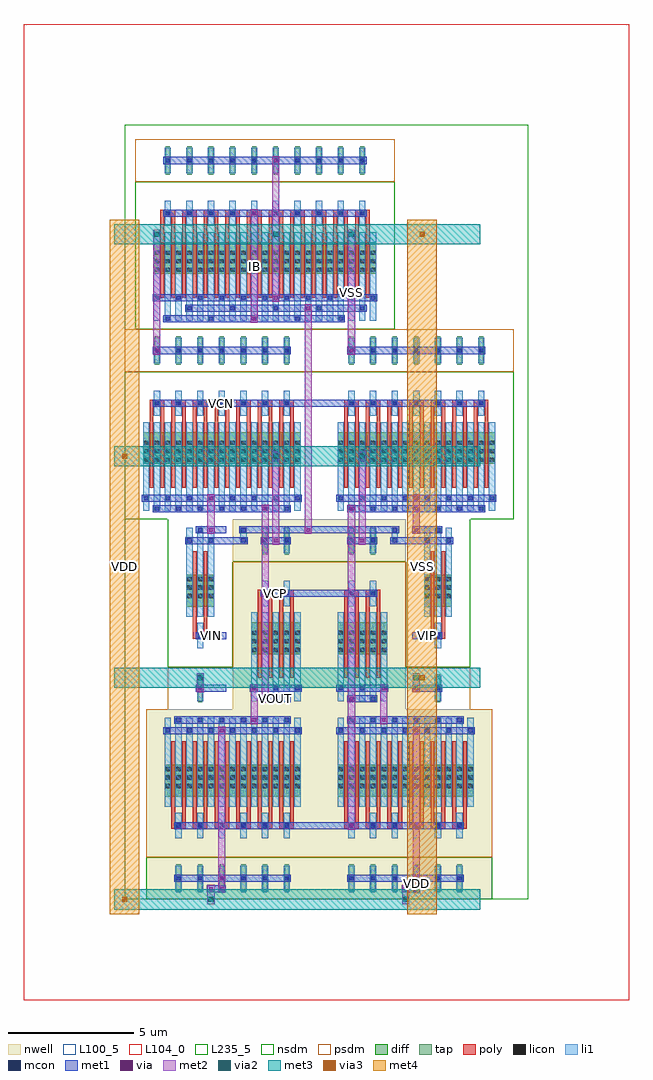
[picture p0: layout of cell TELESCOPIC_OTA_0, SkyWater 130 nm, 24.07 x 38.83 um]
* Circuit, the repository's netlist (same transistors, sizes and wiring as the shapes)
* NGSPICE file created from TELESCOPIC_OTA_0.ext - technology: sky130A

.subckt PMOS_S_86315193_X6_Y1_1774869361 a_230_441# a_200_252# w_0_0#
X0 w_0_0# a_200_252# a_230_441# w_0_0# sky130_fd_pr__pfet_01v8 ad=0.1764 pd=1.54 as=0.1764 ps=1.54 w=1.26 l=0.15 M=12
.ends

.subckt NMOS_4T_67607497_X1_Y1_1774869359 a_230_441# a_200_252# a_147_441# a_241_1232#
X0 a_230_441# a_200_252# a_147_441# a_241_1232# sky130_fd_pr__nfet_01v8 ad=0.1764 pd=1.54 as=0.3339 ps=3.05 w=1.26 l=0.15 M=2
.ends

.subckt SCM_NMOS_71172734_X5_Y1_1774869362 a_402_441# a_200_252# a_147_441#
X0 a_147_441# a_200_252# a_200_252# a_147_441# sky130_fd_pr__nfet_01v8 ad=0.1764 pd=1.54 as=0.1764 ps=1.54 w=1.26 l=0.15 M=10
X1 a_402_441# a_200_252# a_147_441# a_147_441# sky130_fd_pr__nfet_01v8 ad=0.1764 pd=1.54 as=0.1764 ps=1.54 w=1.26 l=0.15 M=10
.ends

.subckt PMOS_4T_36899923_X2_Y1_1774869360 a_230_441# a_200_252# a_147_441# w_0_0#
X0 a_147_441# a_200_252# a_230_441# w_0_0# sky130_fd_pr__pfet_01v8 ad=0.1764 pd=1.54 as=0.1764 ps=1.54 w=1.26 l=0.15 M=4
.ends

.subckt NMOS_4T_35702222_X7_Y1_1774869358 a_230_441# a_200_252# a_147_441# a_241_1232#
X0 a_147_441# a_200_252# a_230_441# a_241_1232# sky130_fd_pr__nfet_01v8 ad=0.1764 pd=1.54 as=0.1764 ps=1.54 w=1.26 l=0.15 M=14
.ends

.subckt TELESCOPIC_OTA_0 IB VCN VOUT VIP VIN VCP VSS VDD
XPMOS_S_86315193_X6_Y1_1774869361_0 m1_1000_1400# m1_1290_560# VDD PMOS_S_86315193_X6_Y1_1774869361
XNMOS_4T_67607497_X1_Y1_1774869359_0 m1_656_2912# VIN li_921_2839# VSS NMOS_4T_67607497_X1_Y1_1774869359
XSCM_NMOS_71172734_X5_Y1_1774869362_0 li_921_2839# IB VSS SCM_NMOS_71172734_X5_Y1_1774869362
XPMOS_S_86315193_X6_Y1_1774869361_1 m1_2032_1400# m1_1290_560# VDD PMOS_S_86315193_X6_Y1_1774869361
XNMOS_4T_67607497_X1_Y1_1774869359_1 m1_2290_2912# VIP li_921_2839# VSS NMOS_4T_67607497_X1_Y1_1774869359
XPMOS_4T_36899923_X2_Y1_1774869360_0 VOUT VCP m1_1000_1400# VDD PMOS_4T_36899923_X2_Y1_1774869360
XPMOS_4T_36899923_X2_Y1_1774869360_1 m1_1290_560# VCP m1_2032_1400# VDD PMOS_4T_36899923_X2_Y1_1774869360
XNMOS_4T_35702222_X7_Y1_1774869358_0 VOUT VCN m1_656_2912# VSS NMOS_4T_35702222_X7_Y1_1774869358
XNMOS_4T_35702222_X7_Y1_1774869358_1 m1_1290_560# VCN m1_2290_2912# VSS NMOS_4T_35702222_X7_Y1_1774869358
.ends

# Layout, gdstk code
from math import pi, radians
import gdstk
lib = gdstk.Library(unit=1e-6, precision=1e-09)
def R(c, l, rs):  # rectangles x0, y0, x1, y1
    for r in rs: c.add(gdstk.rectangle(r[:2], r[2:], *l))
def A(c, l, x, y, w, h, nx, ny, dx, dy):  # array of equal rectangles
    R(c, l, [(x+i*dx, y+j*dy, x+i*dx+w, y+j*dy+h) for i in range(nx) for j in range(ny)])
def P(c, l, *ps):  # polygons
    for p in ps: c.add(gdstk.Polygon(p, *l))
nwell = (64, 20)
diff = (65, 20)
tap = (65, 44)
poly = (66, 20)
licon = (66, 44)
li1 = (67, 20)
mcon = (67, 44)
met1 = (68, 20)
via = (68, 44)
met2 = (69, 20)
via2 = (69, 44)
met3 = (70, 20)
via3 = (70, 44)
met4 = (71, 20)
nsdm = (93, 44)
psdm = (94, 20)
L100_5 = (100, 5)
L104_0 = (104, 0)
L235_5 = (235, 5)

scm_nmos_71172734_x5_y1_ = lib.new_cell('SCM_NMOS_71172734_X5_Y1_1774869362')
R(scm_nmos_71172734_x5_y1_, diff, [(0.735,2.205,9.585,3.465)])
A(scm_nmos_71172734_x5_y1_, tap, 1.205, 6.16, 0.17, 1.12, 10, 1, 0.86, 0)
A(scm_nmos_71172734_x5_y1_, poly, 1, 1.26, 0.15, 3.36, 20, 1, 0.43, 0)
A(scm_nmos_71172734_x5_y1_, poly, 1, 4.485, 0.58, 0.27, 10, 1, 0.86, 0)
A(scm_nmos_71172734_x5_y1_, licon, 0.775, 2.285, 0.17, 0.17, 3, 3, 0.43, 0.34)
A(scm_nmos_71172734_x5_y1_, licon, 1.635, 2.285, 0.17, 0.17, 3, 3, 0.43, 0.34)
A(scm_nmos_71172734_x5_y1_, licon, 2.495, 2.285, 0.17, 0.17, 3, 3, 0.43, 0.34)
A(scm_nmos_71172734_x5_y1_, licon, 3.355, 2.285, 0.17, 0.17, 3, 3, 0.43, 0.34)
A(scm_nmos_71172734_x5_y1_, licon, 4.215, 2.285, 0.17, 0.17, 3, 3, 0.43, 0.34)
A(scm_nmos_71172734_x5_y1_, licon, 5.075, 2.285, 0.17, 0.17, 3, 3, 0.43, 0.34)
A(scm_nmos_71172734_x5_y1_, licon, 5.935, 2.285, 0.17, 0.17, 3, 3, 0.43, 0.34)
A(scm_nmos_71172734_x5_y1_, licon, 6.795, 2.285, 0.17, 0.17, 3, 3, 0.43, 0.34)
A(scm_nmos_71172734_x5_y1_, licon, 7.655, 2.285, 0.17, 0.17, 3, 3, 0.43, 0.34)
A(scm_nmos_71172734_x5_y1_, licon, 8.515, 2.285, 0.17, 0.17, 3, 3, 0.43, 0.34)
A(scm_nmos_71172734_x5_y1_, licon, 1.205, 4.535, 0.17, 0.17, 10, 2, 0.86, 2.1)
A(scm_nmos_71172734_x5_y1_, li1, 0.735, 0.335, 0.25, 3.53, 21, 1, 0.43, 0)
A(scm_nmos_71172734_x5_y1_, li1, 1.165, 4.115, 0.25, 1.01, 10, 2, 0.86, 2.1)
A(scm_nmos_71172734_x5_y1_, mcon, 1.205, 0.335, 0.17, 0.17, 5, 1, 1.72, 0)
A(scm_nmos_71172734_x5_y1_, mcon, 2.065, 0.755, 0.17, 0.17, 5, 1, 1.72, 0)
A(scm_nmos_71172734_x5_y1_, mcon, 0.775, 1.175, 0.17, 0.17, 11, 1, 0.86, 0)
A(scm_nmos_71172734_x5_y1_, mcon, 1.205, 4.535, 0.17, 0.17, 10, 2, 0.86, 2.1)
R(scm_nmos_71172734_x5_y1_, met1, [(1.12,0.28,8.34,0.56), (1.98,0.7,9.2,0.98), (0.69,1.12,9.63,1.4), (1.12,4.48,9.2,4.76), (1.12,6.58,9.2,6.86)])
R(scm_nmos_71172734_x5_y1_, via, [(4.655,0.345,4.805,0.495), (5.515,1.185,5.665,1.335), (4.655,4.545,4.805,4.695), (5.515,6.645,5.665,6.795)])
R(scm_nmos_71172734_x5_y1_, met2, [(4.59,0.26,4.87,4.78), (5.45,1.1,5.73,6.88)])
R(scm_nmos_71172734_x5_y1_, nsdm, [(0,0,10.32,5.88)])
R(scm_nmos_71172734_x5_y1_, psdm, [(0,5.88,10.32,7.56)])
R(scm_nmos_71172734_x5_y1_, L100_5, [(0,0,10.32,7.56)])

pmos_s_86315193_x6_y1_17 = lib.new_cell('PMOS_S_86315193_X6_Y1_1774869361')
R(pmos_s_86315193_x6_y1_17, nwell, [(0,0,6.88,7.56)])
R(pmos_s_86315193_x6_y1_17, diff, [(0.735,2.205,6.145,3.465)])
A(pmos_s_86315193_x6_y1_17, tap, 1.205, 6.16, 0.17, 1.12, 6, 1, 0.86, 0)
A(pmos_s_86315193_x6_y1_17, poly, 1, 1.26, 0.15, 3.36, 12, 1, 0.43, 0)
A(pmos_s_86315193_x6_y1_17, poly, 1, 4.485, 0.58, 0.27, 6, 1, 0.86, 0)
A(pmos_s_86315193_x6_y1_17, licon, 0.775, 2.285, 0.17, 0.17, 3, 3, 0.43, 0.34)
A(pmos_s_86315193_x6_y1_17, licon, 1.635, 2.285, 0.17, 0.17, 3, 3, 0.43, 0.34)
A(pmos_s_86315193_x6_y1_17, licon, 2.495, 2.285, 0.17, 0.17, 3, 3, 0.43, 0.34)
A(pmos_s_86315193_x6_y1_17, licon, 3.355, 2.285, 0.17, 0.17, 3, 3, 0.43, 0.34)
A(pmos_s_86315193_x6_y1_17, licon, 4.215, 2.285, 0.17, 0.17, 3, 3, 0.43, 0.34)
A(pmos_s_86315193_x6_y1_17, licon, 5.075, 2.285, 0.17, 0.17, 3, 3, 0.43, 0.34)
A(pmos_s_86315193_x6_y1_17, licon, 1.205, 4.535, 0.17, 0.17, 6, 2, 0.86, 2.1)
A(pmos_s_86315193_x6_y1_17, li1, 0.735, 0.335, 0.25, 3.53, 13, 1, 0.43, 0)
A(pmos_s_86315193_x6_y1_17, li1, 1.165, 4.115, 0.25, 1.01, 6, 2, 0.86, 2.1)
A(pmos_s_86315193_x6_y1_17, mcon, 1.205, 0.335, 0.17, 0.17, 6, 2, 0.86, 4.2)
A(pmos_s_86315193_x6_y1_17, mcon, 0.775, 0.755, 0.17, 0.17, 7, 1, 0.86, 0)
A(pmos_s_86315193_x6_y1_17, mcon, 1.205, 6.635, 0.17, 0.17, 6, 1, 0.86, 0)
R(pmos_s_86315193_x6_y1_17, met1, [(1.12,0.28,5.76,0.56), (0.69,0.7,6.19,0.98), (1.12,4.48,5.76,4.76), (1.12,6.58,5.76,6.86)])
R(pmos_s_86315193_x6_y1_17, via, [(3.795,0.765,3.945,0.915), (3.795,6.645,3.945,6.795)])
R(pmos_s_86315193_x6_y1_17, met2, [(3.73,0.68,4.01,6.88)])
R(pmos_s_86315193_x6_y1_17, nsdm, [(0,5.88,6.88,7.56)])
R(pmos_s_86315193_x6_y1_17, psdm, [(0,0,6.88,5.88)])
R(pmos_s_86315193_x6_y1_17, L100_5, [(0,0,6.88,7.56)])

nmos_4t_35702222_x7_y1_1 = lib.new_cell('NMOS_4T_35702222_X7_Y1_1774869358')
R(nmos_4t_35702222_x7_y1_1, diff, [(0.735,2.205,7.005,3.465)])
A(nmos_4t_35702222_x7_y1_1, tap, 1.205, 6.16, 0.17, 1.12, 7, 1, 0.86, 0)
A(nmos_4t_35702222_x7_y1_1, poly, 1, 1.26, 0.15, 3.36, 14, 1, 0.43, 0)
A(nmos_4t_35702222_x7_y1_1, poly, 1, 4.485, 0.58, 0.27, 7, 1, 0.86, 0)
A(nmos_4t_35702222_x7_y1_1, licon, 0.775, 2.285, 0.17, 0.17, 3, 3, 0.43, 0.34)
A(nmos_4t_35702222_x7_y1_1, licon, 1.635, 2.285, 0.17, 0.17, 3, 3, 0.43, 0.34)
A(nmos_4t_35702222_x7_y1_1, licon, 2.495, 2.285, 0.17, 0.17, 3, 3, 0.43, 0.34)
A(nmos_4t_35702222_x7_y1_1, licon, 3.355, 2.285, 0.17, 0.17, 3, 3, 0.43, 0.34)
A(nmos_4t_35702222_x7_y1_1, licon, 4.215, 2.285, 0.17, 0.17, 3, 3, 0.43, 0.34)
A(nmos_4t_35702222_x7_y1_1, licon, 5.075, 2.285, 0.17, 0.17, 3, 3, 0.43, 0.34)
A(nmos_4t_35702222_x7_y1_1, licon, 5.935, 2.285, 0.17, 0.17, 3, 3, 0.43, 0.34)
A(nmos_4t_35702222_x7_y1_1, licon, 1.205, 4.535, 0.17, 0.17, 7, 2, 0.86, 2.1)
A(nmos_4t_35702222_x7_y1_1, li1, 0.735, 0.335, 0.25, 3.53, 15, 1, 0.43, 0)
A(nmos_4t_35702222_x7_y1_1, li1, 1.165, 4.115, 0.25, 1.01, 7, 2, 0.86, 2.1)
A(nmos_4t_35702222_x7_y1_1, mcon, 1.205, 0.335, 0.17, 0.17, 7, 2, 0.86, 4.2)
A(nmos_4t_35702222_x7_y1_1, mcon, 0.775, 0.755, 0.17, 0.17, 8, 1, 0.86, 0)
A(nmos_4t_35702222_x7_y1_1, mcon, 1.205, 6.635, 0.17, 0.17, 7, 1, 0.86, 0)
R(nmos_4t_35702222_x7_y1_1, met1, [(1.12,0.28,6.62,0.56), (0.69,0.7,7.05,0.98), (1.12,4.48,6.62,4.76), (1.12,6.58,6.62,6.86)])
R(nmos_4t_35702222_x7_y1_1, nsdm, [(0,0,7.74,5.88)])
R(nmos_4t_35702222_x7_y1_1, psdm, [(0,5.88,7.74,7.56)])
R(nmos_4t_35702222_x7_y1_1, L100_5, [(0,0,7.74,7.56)])

nmos_4t_67607497_x1_y1_1 = lib.new_cell('NMOS_4T_67607497_X1_Y1_1774869359')
R(nmos_4t_67607497_x1_y1_1, diff, [(0.735,2.205,1.845,3.465)])
R(nmos_4t_67607497_x1_y1_1, tap, [(1.205,6.16,1.375,7.28)])
R(nmos_4t_67607497_x1_y1_1, poly, [(1,1.26,1.15,4.62), (1.43,1.26,1.58,4.62), (1,4.485,1.58,4.755)])
A(nmos_4t_67607497_x1_y1_1, licon, 0.775, 2.285, 0.17, 0.17, 3, 3, 0.43, 0.34)
R(nmos_4t_67607497_x1_y1_1, licon, [(1.205,4.535,1.375,4.705), (1.205,6.635,1.375,6.805)])
A(nmos_4t_67607497_x1_y1_1, li1, 0.735, 0.335, 0.25, 3.53, 3, 1, 0.43, 0)
R(nmos_4t_67607497_x1_y1_1, li1, [(1.165,4.115,1.415,5.125), (1.165,6.215,1.415,7.225)])
R(nmos_4t_67607497_x1_y1_1, mcon, [(1.205,0.335,1.375,0.505), (0.775,0.755,0.945,0.925), (1.635,0.755,1.805,0.925), (1.205,4.535,1.375,4.705), (1.205,6.635,1.375,6.805)])
R(nmos_4t_67607497_x1_y1_1, met1, [(0.26,0.28,1.46,0.56), (0.69,0.7,1.89,0.98), (0.26,4.48,1.46,4.76), (0.26,6.58,1.46,6.86)])
R(nmos_4t_67607497_x1_y1_1, nsdm, [(0,0,2.58,5.88)])
R(nmos_4t_67607497_x1_y1_1, psdm, [(0,5.88,2.58,7.56)])
R(nmos_4t_67607497_x1_y1_1, L100_5, [(0,0,2.58,7.56)])

pmos_4t_36899923_x2_y1_1 = lib.new_cell('PMOS_4T_36899923_X2_Y1_1774869360')
R(pmos_4t_36899923_x2_y1_1, nwell, [(0,0,3.44,7.56)])
R(pmos_4t_36899923_x2_y1_1, diff, [(0.735,2.205,2.705,3.465)])
R(pmos_4t_36899923_x2_y1_1, tap, [(1.205,6.16,1.375,7.28), (2.065,6.16,2.235,7.28)])
A(pmos_4t_36899923_x2_y1_1, poly, 1, 1.26, 0.15, 3.36, 4, 1, 0.43, 0)
R(pmos_4t_36899923_x2_y1_1, poly, [(1,4.485,1.58,4.755), (1.86,4.485,2.44,4.755)])
A(pmos_4t_36899923_x2_y1_1, licon, 0.775, 2.285, 0.17, 0.17, 3, 3, 0.43, 0.34)
A(pmos_4t_36899923_x2_y1_1, licon, 1.635, 2.285, 0.17, 0.17, 3, 3, 0.43, 0.34)
R(pmos_4t_36899923_x2_y1_1, licon, [(1.205,4.535,1.375,4.705), (2.065,4.535,2.235,4.705), (1.205,6.635,1.375,6.805), (2.065,6.635,2.235,6.805)])
A(pmos_4t_36899923_x2_y1_1, li1, 0.735, 0.335, 0.25, 3.53, 5, 1, 0.43, 0)
R(pmos_4t_36899923_x2_y1_1, li1, [(1.165,4.115,1.415,5.125), (2.025,4.115,2.275,5.125), (1.165,6.215,1.415,7.225), (2.025,6.215,2.275,7.225)])
A(pmos_4t_36899923_x2_y1_1, mcon, 0.775, 0.755, 0.17, 0.17, 3, 1, 0.86, 0)
R(pmos_4t_36899923_x2_y1_1, mcon, [(1.205,0.335,1.375,0.505), (2.065,0.335,2.235,0.505), (1.205,4.535,1.375,4.705), (2.065,4.535,2.235,4.705), (1.205,6.635,1.375,6.805), (2.065,6.635,2.235,6.805)])
R(pmos_4t_36899923_x2_y1_1, met1, [(1.12,0.28,2.32,0.56), (0.69,0.7,2.75,0.98), (1.12,4.48,2.32,4.76), (1.12,6.58,2.32,6.86)])
R(pmos_4t_36899923_x2_y1_1, nsdm, [(0,5.88,3.44,7.56)])
R(pmos_4t_36899923_x2_y1_1, psdm, [(0,0,3.44,5.88)])
R(pmos_4t_36899923_x2_y1_1, L100_5, [(0,0,3.44,7.56)])

telescopic_ota_0 = lib.new_cell('TELESCOPIC_OTA_0')
R(telescopic_ota_0, li1, [(4.605,14.195,4.855,14.365), (4.605,14.195,4.855,14.365), (4.605,14.195,4.855,14.365), (4.605,14.195,4.855,14.365), (10.625,14.195,10.875,14.365), (10.625,14.195,10.875,14.365), (10.625,14.195,10.875,14.365), (10.625,14.195,10.875,14.365), (4.605,14.28,4.855,14.7), (10.625,14.28,10.875,14.7), (4.605,14.615,4.855,14.785), (4.605,14.615,4.855,14.785), (4.605,14.615,4.855,14.785), (4.605,14.615,4.855,14.785), (10.625,14.615,10.875,14.785), (10.625,14.615,10.875,14.785), (10.625,14.615,10.875,14.785), (10.625,14.615,10.875,14.785)])
R(telescopic_ota_0, mcon, [(4.645,14.195,4.815,14.365), (4.645,14.195,4.815,14.365), (4.645,14.195,4.815,14.365), (4.645,14.195,4.815,14.365), (10.665,14.195,10.835,14.365), (10.665,14.195,10.835,14.365), (10.665,14.195,10.835,14.365), (10.665,14.195,10.835,14.365), (4.645,14.615,4.815,14.785), (4.645,14.615,4.815,14.785), (4.645,14.615,4.815,14.785), (4.645,14.615,4.815,14.785), (10.665,14.615,10.835,14.785), (10.665,14.615,10.835,14.785), (10.665,14.615,10.835,14.785), (10.665,14.615,10.835,14.785)])
R(telescopic_ota_0, met1, [(3.28,0.28,3.6,0.56), (3.28,0.28,3.6,0.56), (3.28,0.28,3.6,0.56), (3.28,0.28,3.6,0.56), (3.44,0.28,3.87,0.56), (3.71,0.28,4.03,0.56), (3.71,0.28,4.03,0.56), (3.71,0.28,4.03,0.56), (3.71,0.28,4.03,0.56), (11.02,0.28,11.34,0.56), (11.02,0.28,11.34,0.56), (11.02,0.28,11.34,0.56), (11.02,0.28,11.34,0.56), (11.02,0.28,11.34,0.56), (11.18,0.28,11.61,0.56), (11.45,0.28,11.77,0.56), (11.45,0.28,11.77,0.56), (11.45,0.28,11.77,0.56), (11.45,0.28,11.77,0.56), (11.45,0.28,11.77,0.56), (6.45,2.8,9.03,3.08), (8.87,2.8,9.19,3.08), (8.87,2.8,9.19,3.08), (8.87,2.8,9.19,3.08), (8.87,2.8,9.19,3.08), (5,7,5.32,7.28), (5,7,5.32,7.28), (10.16,7,10.48,7.28), (10.16,7,10.48,7.28), (5.43,7.84,5.75,8.12), (5.43,7.84,5.75,8.12), (8.87,7.84,9.19,8.12), (8.87,7.84,9.19,8.12), (8.87,7.84,9.19,8.12), (8.87,7.84,9.19,8.12), (2.85,8.26,3.17,8.54), (2.85,8.26,3.17,8.54), (5,8.26,5.32,8.54), (5,8.26,5.32,8.54), (10.16,8.26,10.48,8.54), (10.16,8.26,10.48,8.54), (11.45,8.26,11.77,8.54), (11.45,8.26,11.77,8.54), (11.45,8.26,11.77,8.54), (6.45,12.04,9.03,12.32), (3.44,14.14,4.73,14.42), (4.56,14.14,4.9,14.42), (4.56,14.14,4.9,14.42), (4.56,14.14,4.9,14.42), (4.56,14.14,4.9,14.42), (5.86,14.14,6.18,14.42), (5.86,14.14,6.18,14.42), (9.3,14.14,9.62,14.42), (9.3,14.14,9.62,14.42), (9.3,14.14,9.62,14.42), (10.58,14.14,10.92,14.42), (10.58,14.14,10.92,14.42), (10.58,14.14,10.92,14.42), (10.58,14.14,10.92,14.42), (10.75,14.14,12.04,14.42), (3.28,14.56,3.6,14.84), (3.28,14.56,3.6,14.84), (4.56,14.56,4.9,14.84), (4.56,14.56,4.9,14.84), (4.56,14.56,4.9,14.84), (4.56,14.56,4.9,14.84), (4.73,14.56,10.75,14.84), (7.15,14.56,7.47,14.84), (7.15,14.56,7.47,14.84), (10.58,14.56,10.92,14.84), (10.58,14.56,10.92,14.84), (10.58,14.56,10.92,14.84), (10.58,14.56,10.92,14.84), (11.45,14.56,11.77,14.84), (11.45,14.56,11.77,14.84), (5.43,15.4,5.75,15.68), (5.43,15.4,5.75,15.68), (8.87,15.4,9.19,15.68), (8.87,15.4,9.19,15.68), (3.28,15.82,3.6,16.1), (3.28,15.82,3.6,16.1), (11.45,15.82,11.77,16.1), (11.45,15.82,11.77,16.1), (6.45,19.6,9.03,19.88), (1.13,21.7,1.45,21.98), (1.13,21.7,1.45,21.98), (1.13,21.7,1.45,21.98), (1.13,21.7,1.45,21.98), (8.87,21.7,9.19,21.98), (8.87,21.7,9.19,21.98), (8.87,21.7,9.19,21.98), (8.87,21.7,9.19,21.98), (8.87,21.7,9.19,21.98), (7.15,23.38,7.47,23.66), (7.15,23.38,7.47,23.66)])
P(telescopic_ota_0, met1, [(0,0),(0,0),(0,0),(0,0)],
  [(0,0),(0,0),(0,0),(0,0)],
  [(0,0),(0,0),(0,0),(0,0)],
  [(0,0),(0,0),(0,0),(0,0)],
  [(0,0),(0,0),(0,0),(0,0)],
  [(0,0),(0,0),(0,0),(0,0)],
  [(0,0),(0,0),(0,0),(0,0)],
  [(0,0),(0,0),(0,0),(0,0)],
  [(0,0),(0,0),(0,0),(0,0)],
  [(0,0),(0,0),(0,0),(0,0)],
  [(0,0),(0,0),(0,0),(0,0)],
  [(0,0),(0,0),(0,0),(0,0)],
  [(0,0),(0,0),(0,0),(0,0)],
  [(0,0),(0,0),(0,0),(0,0)],
  [(0,0),(0,0),(0,0),(0,0)],
  [(0,0),(0,0),(0,0),(0,0)],
  [(0,0),(0,0),(0,0),(0,0)],
  [(0,0),(0,0),(0,0),(0,0)],
  [(0,0),(0,0),(0,0),(0,0)],
  [(0,0),(0,0),(0,0),(0,0)],
  [(0,0),(0,0),(0,0),(0,0)],
  [(0,0),(0,0),(0,0),(0,0)],
  [(0,0),(0,0),(0,0),(0,0)],
  [(0,0),(0,0),(0,0),(0,0)],
  [(0,0),(0,0),(0,0),(0,0)],
  [(0,0),(0,0),(0,0),(0,0)],
  [(0,0),(0,0),(0,0),(0,0)],
  [(0,0),(0,0),(0,0),(0,0)],
  [(0,0),(0,0),(0,0),(0,0)],
  [(0,0),(0,0),(0,0),(0,0)],
  [(0,0),(0,0),(0,0),(0,0)],
  [(0,0),(0,0),(0,0),(0,0)],
  [(0,0),(0,0),(0,0),(0,0)],
  [(0,0),(0,0),(0,0),(0,0)])
R(telescopic_ota_0, via, [(3.365,0.345,3.515,0.495), (3.365,0.345,3.515,0.495), (3.365,0.345,3.515,0.495), (3.365,0.345,3.515,0.495), (3.795,0.345,3.945,0.495), (3.795,0.345,3.945,0.495), (3.795,0.345,3.945,0.495), (3.795,0.345,3.945,0.495), (11.105,0.345,11.255,0.495), (11.105,0.345,11.255,0.495), (11.105,0.345,11.255,0.495), (11.105,0.345,11.255,0.495), (11.105,0.345,11.255,0.495), (11.535,0.345,11.685,0.495), (11.535,0.345,11.685,0.495), (11.535,0.345,11.685,0.495), (11.535,0.345,11.685,0.495), (11.535,0.345,11.685,0.495), (8.955,2.865,9.105,3.015), (8.955,2.865,9.105,3.015), (8.955,2.865,9.105,3.015), (8.955,2.865,9.105,3.015), (5.085,7.065,5.235,7.215), (5.085,7.065,5.235,7.215), (10.245,7.065,10.395,7.215), (10.245,7.065,10.395,7.215), (5.515,7.905,5.665,8.055), (5.515,7.905,5.665,8.055), (8.955,7.905,9.105,8.055), (8.955,7.905,9.105,8.055), (8.955,7.905,9.105,8.055), (8.955,7.905,9.105,8.055), (2.935,8.325,3.085,8.475), (2.935,8.325,3.085,8.475), (5.085,8.325,5.235,8.475), (5.085,8.325,5.235,8.475), (10.245,8.325,10.395,8.475), (10.245,8.325,10.395,8.475), (11.535,8.325,11.685,8.475), (11.535,8.325,11.685,8.475), (11.535,8.325,11.685,8.475), (5.945,14.205,6.095,14.355), (5.945,14.205,6.095,14.355), (9.385,14.205,9.535,14.355), (9.385,14.205,9.535,14.355), (9.385,14.205,9.535,14.355), (3.365,14.625,3.515,14.775), (3.365,14.625,3.515,14.775), (7.235,14.625,7.385,14.775), (7.235,14.625,7.385,14.775), (11.535,14.625,11.685,14.775), (11.535,14.625,11.685,14.775), (5.515,15.465,5.665,15.615), (5.515,15.465,5.665,15.615), (8.955,15.465,9.105,15.615), (8.955,15.465,9.105,15.615), (3.365,15.885,3.515,16.035), (3.365,15.885,3.515,16.035), (11.535,15.885,11.685,16.035), (11.535,15.885,11.685,16.035), (1.215,21.765,1.365,21.915), (1.215,21.765,1.365,21.915), (1.215,21.765,1.365,21.915), (1.215,21.765,1.365,21.915), (8.955,21.765,9.105,21.915), (8.955,21.765,9.105,21.915), (8.955,21.765,9.105,21.915), (8.955,21.765,9.105,21.915), (8.955,21.765,9.105,21.915), (7.235,23.445,7.385,23.595), (7.235,23.445,7.385,23.595)])
R(telescopic_ota_0, met2, [(3.3,-0.185,3.58,0.185), (3.3,-0.185,3.58,0.185), (3.3,-0.185,3.58,0.185), (3.3,-0.185,3.58,0.185), (11.04,-0.185,11.32,0.185), (11.04,-0.185,11.32,0.185), (11.04,-0.185,11.32,0.185), (11.04,-0.185,11.32,0.185), (11.04,-0.185,11.32,0.185), (3.3,0,3.58,0.42), (11.04,0,11.32,0.42), (3.3,0.26,3.58,0.58), (3.3,0.26,3.58,0.58), (3.3,0.26,3.58,0.58), (3.3,0.26,3.58,0.58), (3.73,0.26,4.01,0.58), (3.73,0.26,4.01,0.58), (3.73,0.26,4.01,0.58), (3.73,0.26,4.01,0.58), (11.04,0.26,11.32,0.58), (11.04,0.26,11.32,0.58), (11.04,0.26,11.32,0.58), (11.04,0.26,11.32,0.58), (11.04,0.26,11.32,0.58), (11.47,0.26,11.75,0.58), (11.47,0.26,11.75,0.58), (11.47,0.26,11.75,0.58), (11.47,0.26,11.75,0.58), (11.47,0.26,11.75,0.58), (3.73,0.42,4.01,0.84), (11.47,0.42,11.75,0.84), (8.89,2.78,9.17,3.1), (8.89,2.78,9.17,3.1), (8.89,2.78,9.17,3.1), (8.89,2.78,9.17,3.1), (8.89,2.94,9.17,7.98), (5.02,6.98,5.3,7.3), (5.02,6.98,5.3,7.3), (10.18,6.98,10.46,7.3), (10.18,6.98,10.46,7.3), (5.02,7.14,5.3,8.4), (10.18,7.14,10.46,8.4), (5.45,7.82,5.73,8.14), (5.45,7.82,5.73,8.14), (8.89,7.82,9.17,8.14), (8.89,7.82,9.17,8.14), (8.89,7.82,9.17,8.14), (8.89,7.82,9.17,8.14), (5.45,7.98,5.73,15.54), (8.89,7.98,9.17,15.54), (2.87,8.24,3.15,8.56), (2.87,8.24,3.15,8.56), (5.02,8.24,5.3,8.56), (5.02,8.24,5.3,8.56), (10.18,8.24,10.46,8.56), (10.18,8.24,10.46,8.56), (11.47,8.24,11.75,8.56), (11.47,8.24,11.75,8.56), (11.47,8.24,11.75,8.56), (2.87,8.4,3.15,8.82), (11.47,8.4,11.75,8.82), (2.87,8.635,3.15,9.005), (2.87,8.635,3.15,9.005), (11.47,8.635,11.75,9.005), (11.47,8.635,11.75,9.005), (11.47,8.635,11.75,9.005), (5.88,14.12,6.16,14.44), (5.88,14.12,6.16,14.44), (9.32,14.12,9.6,14.44), (9.32,14.12,9.6,14.44), (9.32,14.12,9.6,14.44), (5.88,14.28,6.16,17.64), (9.32,14.28,9.6,17.64), (3.3,14.54,3.58,14.86), (3.3,14.54,3.58,14.86), (7.17,14.54,7.45,14.86), (7.17,14.54,7.45,14.86), (11.47,14.54,11.75,14.86), (11.47,14.54,11.75,14.86), (3.3,14.7,3.58,15.96), (7.17,14.7,7.45,23.52), (11.47,14.7,11.75,15.96), (5.45,15.38,5.73,15.7), (5.45,15.38,5.73,15.7), (8.89,15.38,9.17,15.7), (8.89,15.38,9.17,15.7), (3.3,15.8,3.58,16.12), (3.3,15.8,3.58,16.12), (11.47,15.8,11.75,16.12), (11.47,15.8,11.75,16.12), (5.88,17.455,6.16,17.825), (5.88,17.455,6.16,17.825), (9.32,17.455,9.6,17.825), (9.32,17.455,9.6,17.825), (9.32,17.455,9.6,17.825), (1.15,21.68,1.43,22), (1.15,21.68,1.43,22), (1.15,21.68,1.43,22), (1.15,21.68,1.43,22), (8.89,21.68,9.17,22), (8.89,21.68,9.17,22), (8.89,21.68,9.17,22), (8.89,21.68,9.17,22), (8.89,21.68,9.17,22), (1.15,21.84,1.43,26.46), (8.89,21.84,9.17,26.46), (7.17,23.36,7.45,23.68), (7.17,23.36,7.45,23.68), (1.15,26.275,1.43,26.645), (1.15,26.275,1.43,26.645), (1.15,26.275,1.43,26.645), (1.15,26.275,1.43,26.645), (5.88,26.275,6.16,26.645), (5.88,26.275,6.16,26.645), (5.88,26.275,6.16,26.645), (5.88,26.275,6.16,26.645), (5.88,26.275,6.16,26.645), (5.88,26.275,6.16,26.645), (8.89,26.275,9.17,26.645), (8.89,26.275,9.17,26.645), (8.89,26.275,9.17,26.645), (8.89,26.275,9.17,26.645), (8.89,26.275,9.17,26.645)])
P(telescopic_ota_0, met2, [(0,0),(0,0),(0,0),(0,0)],
  [(0,0),(0,0),(0,0),(0,0)],
  [(0,0),(0,0),(0,0),(0,0)],
  [(0,0),(0,0),(0,0),(0,0)],
  [(0,0),(0,0),(0,0),(0,0)])
R(telescopic_ota_0, via2, [(3.34,-0.1,3.54,0.1), (3.34,-0.1,3.54,0.1), (3.34,-0.1,3.54,0.1), (3.34,-0.1,3.54,0.1), (11.08,-0.1,11.28,0.1), (11.08,-0.1,11.28,0.1), (11.08,-0.1,11.28,0.1), (11.08,-0.1,11.28,0.1), (11.08,-0.1,11.28,0.1), (2.91,8.72,3.11,8.92), (2.91,8.72,3.11,8.92), (11.51,8.72,11.71,8.92), (11.51,8.72,11.71,8.92), (11.51,8.72,11.71,8.92), (5.92,17.54,6.12,17.74), (5.92,17.54,6.12,17.74), (9.36,17.54,9.56,17.74), (9.36,17.54,9.56,17.74), (9.36,17.54,9.56,17.74), (1.19,26.36,1.39,26.56), (1.19,26.36,1.39,26.56), (1.19,26.36,1.39,26.56), (1.19,26.36,1.39,26.56), (5.92,26.36,6.12,26.56), (5.92,26.36,6.12,26.56), (5.92,26.36,6.12,26.56), (5.92,26.36,6.12,26.56), (5.92,26.36,6.12,26.56), (5.92,26.36,6.12,26.56), (8.93,26.36,9.13,26.56), (8.93,26.36,9.13,26.56), (8.93,26.36,9.13,26.56), (8.93,26.36,9.13,26.56), (8.93,26.36,9.13,26.56)])
A(telescopic_ota_0, met3, -0.4, -0.4, 4.24, 0.8, 3, 4, 3.44, 8.82)
A(telescopic_ota_0, met3, 9.92, -0.4, 2.32, 0.8, 1, 4, 0, 8.82)
A(telescopic_ota_0, met3, 11.44, -0.4, 2.72, 0.8, 1, 4, 0, 8.82)
R(telescopic_ota_0, met3, [(-0.165,-0.4,0.165,0.4), (3.275,-0.4,3.605,0.4), (3.275,-0.4,3.605,0.4), (3.275,-0.4,3.605,0.4), (3.275,-0.4,3.605,0.4), (11.015,-0.4,11.345,0.4), (11.015,-0.4,11.345,0.4), (11.015,-0.4,11.345,0.4), (11.015,-0.4,11.345,0.4), (11.015,-0.4,11.345,0.4), (2.845,8.42,3.175,9.22), (2.845,8.42,3.175,9.22), (11.445,8.42,11.775,9.22), (11.445,8.42,11.775,9.22), (11.445,8.42,11.775,9.22), (11.675,8.42,12.005,9.22), (-0.165,17.24,0.165,18.04), (5.855,17.24,6.185,18.04), (5.855,17.24,6.185,18.04), (9.295,17.24,9.625,18.04), (9.295,17.24,9.625,18.04), (9.295,17.24,9.625,18.04), (1.125,26.06,1.455,26.86), (1.125,26.06,1.455,26.86), (1.125,26.06,1.455,26.86), (1.125,26.06,1.455,26.86), (5.855,26.06,6.185,26.86), (5.855,26.06,6.185,26.86), (5.855,26.06,6.185,26.86), (5.855,26.06,6.185,26.86), (5.855,26.06,6.185,26.86), (5.855,26.06,6.185,26.86), (8.865,26.06,9.195,26.86), (8.865,26.06,9.195,26.86), (8.865,26.06,9.195,26.86), (8.865,26.06,9.195,26.86), (8.865,26.06,9.195,26.86), (11.675,26.06,12.005,26.86)])
R(telescopic_ota_0, via3, [(-0.1,-0.1,0.1,0.1), (11.74,8.72,11.94,8.92), (-0.1,17.54,0.1,17.74), (11.74,26.36,11.94,26.56)])
A(telescopic_ota_0, met4, -0.59, -0.59, 1.18, 10, 1, 3, 0, 8.82)
A(telescopic_ota_0, met4, 11.25, -0.59, 1.18, 10, 1, 3, 0, 8.82)
R(telescopic_ota_0, met4, [(-0.59,-0.165,0.59,0.165), (11.25,8.655,12.43,8.985), (-0.59,17.475,0.59,17.805), (11.25,26.295,12.43,26.625)])
R(telescopic_ota_0, L104_0, [(-4,-4,20.07,34.83)])
R(telescopic_ota_0, L235_5, [(0,0,16.07,30.83)])
telescopic_ota_0.add(gdstk.Reference(scm_nmos_71172734_x5_y1_, (0.43,22.68)))
telescopic_ota_0.add(gdstk.Reference(pmos_s_86315193_x6_y1_17, (7.74,7.56), x_reflection=True))
telescopic_ota_0.add(gdstk.Reference(pmos_s_86315193_x6_y1_17, (7.74,7.56), rotation=pi))
telescopic_ota_0.add(gdstk.Reference(nmos_4t_35702222_x7_y1_1, (7.74,15.12)))
telescopic_ota_0.add(gdstk.Reference(nmos_4t_35702222_x7_y1_1, (7.74,15.12), rotation=pi, x_reflection=True))
telescopic_ota_0.add(gdstk.Reference(nmos_4t_67607497_x1_y1_1, (11.18,15.12), x_reflection=True))
telescopic_ota_0.add(gdstk.Reference(nmos_4t_67607497_x1_y1_1, (4.3,15.12), rotation=pi))
telescopic_ota_0.add(gdstk.Reference(pmos_4t_36899923_x2_y1_1, (7.74,7.56)))
telescopic_ota_0.add(gdstk.Reference(pmos_4t_36899923_x2_y1_1, (7.74,7.56), rotation=pi, x_reflection=True))
telescopic_ota_0.add(gdstk.Label('IB', (5.16,25.2), layer=69, texttype=5))
telescopic_ota_0.add(gdstk.Label('VCN', (3.87,19.74), layer=68, texttype=5))
telescopic_ota_0.add(gdstk.Label('VOUT', (6.02,7.98), layer=68, texttype=5))
telescopic_ota_0.add(gdstk.Label('VIP', (12.04,10.5), layer=68, texttype=5))
telescopic_ota_0.add(gdstk.Label('VIN', (3.44,10.5), layer=68, texttype=5))
telescopic_ota_0.add(gdstk.Label('VCP', (6.02,12.18), layer=68, texttype=5))
telescopic_ota_0.add(gdstk.Label('VSS', (11.84,13.23), layer=71, texttype=5))
telescopic_ota_0.add(gdstk.Label('VSS', (11.84,13.23), layer=71, texttype=5))
telescopic_ota_0.add(gdstk.Label('VSS', (11.84,13.23), layer=71, texttype=5))
telescopic_ota_0.add(gdstk.Label('VSS', (9.03,24.15), layer=69, texttype=5))
telescopic_ota_0.add(gdstk.Label('VSS', (11.84,13.23), layer=71, texttype=5))
telescopic_ota_0.add(gdstk.Label('VSS', (11.84,13.23), layer=71, texttype=5))
telescopic_ota_0.add(gdstk.Label('VSS', (11.84,13.23), layer=71, texttype=5))
telescopic_ota_0.add(gdstk.Label('VSS', (11.84,13.23), layer=71, texttype=5))
telescopic_ota_0.add(gdstk.Label('VSS', (11.84,13.23), layer=71, texttype=5))
telescopic_ota_0.add(gdstk.Label('VSS', (11.84,13.23), layer=71, texttype=5))
telescopic_ota_0.add(gdstk.Label('VSS', (11.84,13.23), layer=71, texttype=5))
telescopic_ota_0.add(gdstk.Label('VSS', (11.84,13.23), layer=71, texttype=5))
telescopic_ota_0.add(gdstk.Label('VSS', (11.84,13.23), layer=71, texttype=5))
telescopic_ota_0.add(gdstk.Label('VSS', (11.84,13.23), layer=71, texttype=5))
telescopic_ota_0.add(gdstk.Label('VSS', (11.84,13.23), layer=71, texttype=5))
telescopic_ota_0.add(gdstk.Label('VDD', (11.61,0.63), layer=69, texttype=5))
telescopic_ota_0.add(gdstk.Label('VDD', (0,13.23), layer=71, texttype=5))
telescopic_ota_0.add(gdstk.Label('VDD', (0,13.23), layer=71, texttype=5))
telescopic_ota_0.add(gdstk.Label('VDD', (0,13.23), layer=71, texttype=5))
telescopic_ota_0.add(gdstk.Label('VDD', (0,13.23), layer=71, texttype=5))
telescopic_ota_0.add(gdstk.Label('VDD', (0,13.23), layer=71, texttype=5))
telescopic_ota_0.add(gdstk.Label('VDD', (0,13.23), layer=71, texttype=5))
telescopic_ota_0.add(gdstk.Label('VDD', (0,13.23), layer=71, texttype=5))
telescopic_ota_0.add(gdstk.Label('VDD', (0,13.23), layer=71, texttype=5))
telescopic_ota_0.add(gdstk.Label('VDD', (0,13.23), layer=71, texttype=5))
telescopic_ota_0.add(gdstk.Label('VDD', (0,13.23), layer=71, texttype=5))
telescopic_ota_0.add(gdstk.Label('VDD', (0,13.23), layer=71, texttype=5))
telescopic_ota_0.add(gdstk.Label('VDD', (0,13.23), layer=71, texttype=5))
telescopic_ota_0.add(gdstk.Label('VDD', (0,13.23), layer=71, texttype=5))
telescopic_ota_0.add(gdstk.Label('VDD', (0,13.23), layer=71, texttype=5))

lib.write_gds('TELESCOPIC_OTA_0.gds')
